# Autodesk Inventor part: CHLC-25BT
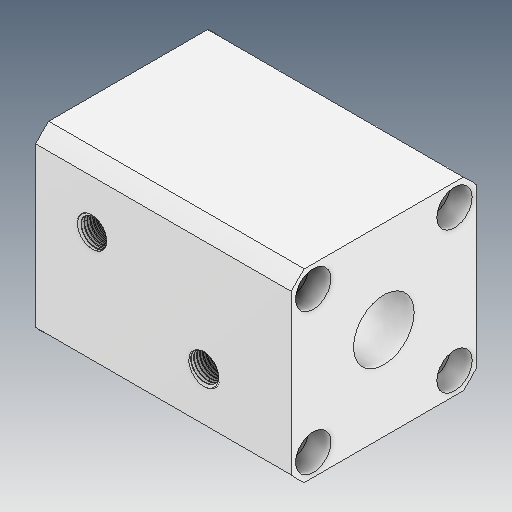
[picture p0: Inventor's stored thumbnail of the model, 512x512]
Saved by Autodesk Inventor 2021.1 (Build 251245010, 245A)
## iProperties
Created: 2021-05
Part Number: CHLC-25BT
Material: Ogólny
Document SubType Name: Modeling
Designer: user
Density: 1 g/cm^3
Appearance: Domyślna
Author: user
Revision Number: ÈÎºÎ
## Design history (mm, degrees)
feature "NONE"
node "Bryła1"
